VERSION 5.8 ;
BUSBITCHARS "[]" ;
DIVIDERCHAR "/" ;
UNITS
    DATABASE MICRONS 2000 ;
END UNITS

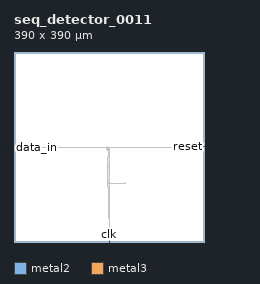
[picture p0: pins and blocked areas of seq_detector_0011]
MACRO seq_detector_0011
  FOREIGN seq_detector_0011 0 0 ;
  CLASS BLOCK ;
  SIZE 390 BY 390 ;
  PIN clk
    DIRECTION INPUT ;
    USE SIGNAL ;
    PORT
      LAYER metal2 ;
        RECT  195.38 0 195.45 0.07 ;
    END
  END clk
  PIN data_in
    DIRECTION INPUT ;
    USE SIGNAL ;
    PORT
      LAYER metal3 ;
        RECT  0 194.915 0.07 194.985 ;
    END
  END data_in
  PIN detected
    DIRECTION OUTPUT ;
    USE SIGNAL ;
    PORT
      LAYER metal2 ;
        RECT  195 0 195.07 0.07 ;
    END
  END detected
  PIN reset
    DIRECTION INPUT ;
    USE SIGNAL ;
    PORT
      LAYER metal3 ;
        RECT  389.93 195.195 390 195.265 ;
    END
  END reset
  OBS
    LAYER metal1 ;
     RECT  190.57 190.315 191.14 191.885 ;
     RECT  191.14 187.515 191.9 191.885 ;
     RECT  193.23 153.915 193.8 155.485 ;
     RECT  193.8 120.315 194.37 121.885 ;
     RECT  191.9 187.515 194.75 193.285 ;
     RECT  194.75 188.915 194.94 193.285 ;
     RECT  194.94 190.315 195.32 193.285 ;
     RECT  195.32 190.315 195.7 194.685 ;
     RECT  193.8 47.515 197.03 49.085 ;
     RECT  195.7 190.315 197.03 191.885 ;
     RECT  228.76 120.315 229.33 121.885 ;
    LAYER metal2 ;
     RECT  195 0.035 195.45 14.215 ;
     RECT  195 14.215 195.83 47.88 ;
     RECT  195 47.88 196.97 48.02 ;
     RECT  195 48.02 195.83 48.3 ;
     RECT  193.29 48.3 195.83 113.965 ;
     RECT  228.82 120.54 228.89 120.82 ;
     RECT  228.82 120.82 229.27 120.96 ;
     RECT  228.82 120.96 228.89 121.24 ;
     RECT  192.91 113.965 195.83 153.935 ;
     RECT  192.91 153.935 195.45 174.16 ;
     RECT  193.1 174.16 195.45 188.3 ;
     RECT  191.96 188.3 195.45 189.56 ;
     RECT  191.58 189.56 195.45 190.68 ;
     RECT  191.58 190.68 196.97 190.82 ;
     RECT  191.58 190.82 195.64 191.1 ;
     RECT  191.39 191.1 195.64 192.045 ;
     RECT  191.96 192.045 195.64 192.5 ;
     RECT  192.15 192.5 195.64 193.48 ;
     RECT  192.15 193.48 195.45 194.04 ;
     RECT  192.15 194.04 192.22 195.02 ;
    LAYER metal3 ;
     RECT  191.545 189.875 191.735 189.945 ;
     RECT  191.735 189.735 191.925 189.945 ;
     RECT  0.035 194.915 191.925 194.985 ;
     RECT  191.925 189.735 192.115 194.985 ;
     RECT  192.115 189.455 192.15 194.985 ;
     RECT  192.15 189.315 192.255 194.985 ;
     RECT  192.255 189.315 192.305 192.465 ;
     RECT  192.875 174.055 193.395 174.125 ;
     RECT  193.255 121.555 194.205 121.625 ;
     RECT  194.205 120.575 194.345 121.625 ;
     RECT  193.255 48.335 194.725 48.405 ;
     RECT  192.305 188.755 194.725 192.465 ;
     RECT  194.725 190.715 195.345 192.465 ;
     RECT  195.345 190.715 195.675 194.005 ;
     RECT  194.965 74.095 195.865 74.165 ;
     RECT  194.965 47.915 197.005 47.985 ;
     RECT  195.675 190.715 197.005 190.785 ;
     RECT  194.345 120.575 228.925 120.925 ;
     RECT  228.925 120.855 229.305 120.925 ;
     RECT  195.675 193.935 389.82 194.005 ;
     RECT  389.82 193.935 389.965 195.265 ;
     RECT  389.965 193.935 390 195.125 ;
  END
END seq_detector_0011
END LIBRARY
